One B-rep face of a CAD part: STEP entity #22778.
In plain terms, the planar face has unit normal (0, 0, -1).
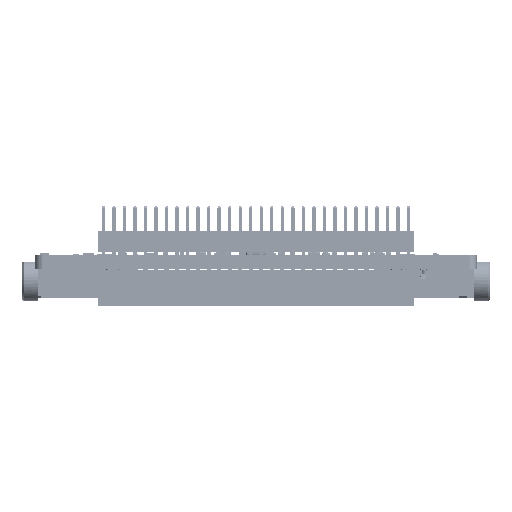
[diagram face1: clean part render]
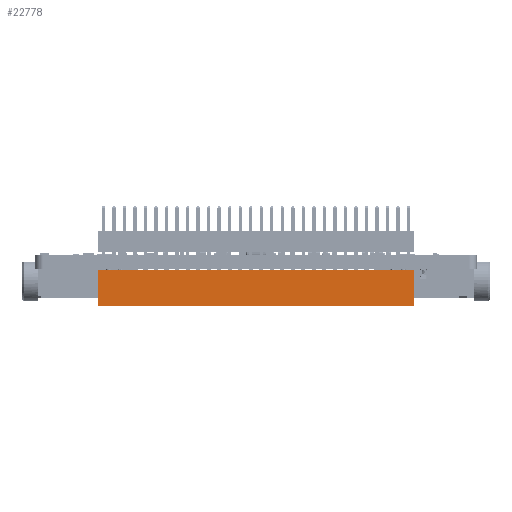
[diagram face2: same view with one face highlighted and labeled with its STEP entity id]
Its self-contained STEP definition (entity closure, numbers rounded to 3 decimals):
#15181 = VERTEX_POINT('',#15182);
#15182 = CARTESIAN_POINT('',(-19.107,4.369,-1.664));
#15188 = EDGE_CURVE('',#15181,#15189,#15191,.T.);
#15189 = VERTEX_POINT('',#15190);
#15190 = CARTESIAN_POINT('',(-19.107,0.,-1.664));
#15191 = LINE('',#15192,#15193);
#15192 = CARTESIAN_POINT('',(-19.107,4.369,-1.664));
#15193 = VECTOR('',#15194,1.);
#15194 = DIRECTION('',(0.,-1.,0.));
#22693 = VERTEX_POINT('',#22694);
#22694 = CARTESIAN_POINT('',(19.107,0.,-1.664));
#22700 = EDGE_CURVE('',#22701,#22693,#22703,.T.);
#22701 = VERTEX_POINT('',#22702);
#22702 = CARTESIAN_POINT('',(19.107,4.369,-1.664));
#22703 = LINE('',#22704,#22705);
#22704 = CARTESIAN_POINT('',(19.107,4.369,-1.664));
#22705 = VECTOR('',#22706,1.);
#22706 = DIRECTION('',(0.,-1.,0.));
#22767 = EDGE_CURVE('',#22693,#15189,#22768,.T.);
#22768 = LINE('',#22769,#22770);
#22769 = CARTESIAN_POINT('',(19.107,0.,-1.664));
#22770 = VECTOR('',#22771,1.);
#22771 = DIRECTION('',(-1.,0.,0.));
#22778 = ADVANCED_FACE('',(#22779),#22790,.F.);
#22779 = FACE_BOUND('',#22780,.T.);
#22780 = EDGE_LOOP('',(#22781,#22782,#22783,#22789));
#22781 = ORIENTED_EDGE('',*,*,#22767,.T.);
#22782 = ORIENTED_EDGE('',*,*,#15188,.F.);
#22783 = ORIENTED_EDGE('',*,*,#22784,.F.);
#22784 = EDGE_CURVE('',#22701,#15181,#22785,.T.);
#22785 = LINE('',#22786,#22787);
#22786 = CARTESIAN_POINT('',(19.107,4.369,-1.664));
#22787 = VECTOR('',#22788,1.);
#22788 = DIRECTION('',(-1.,0.,0.));
#22789 = ORIENTED_EDGE('',*,*,#22700,.T.);
#22790 = PLANE('',#22791);
#22791 = AXIS2_PLACEMENT_3D('',#22792,#22793,#22794);
#22792 = CARTESIAN_POINT('',(19.107,4.369,-1.664));
#22793 = DIRECTION('',(0.,0.,1.));
#22794 = DIRECTION('',(1.,0.,-0.));
